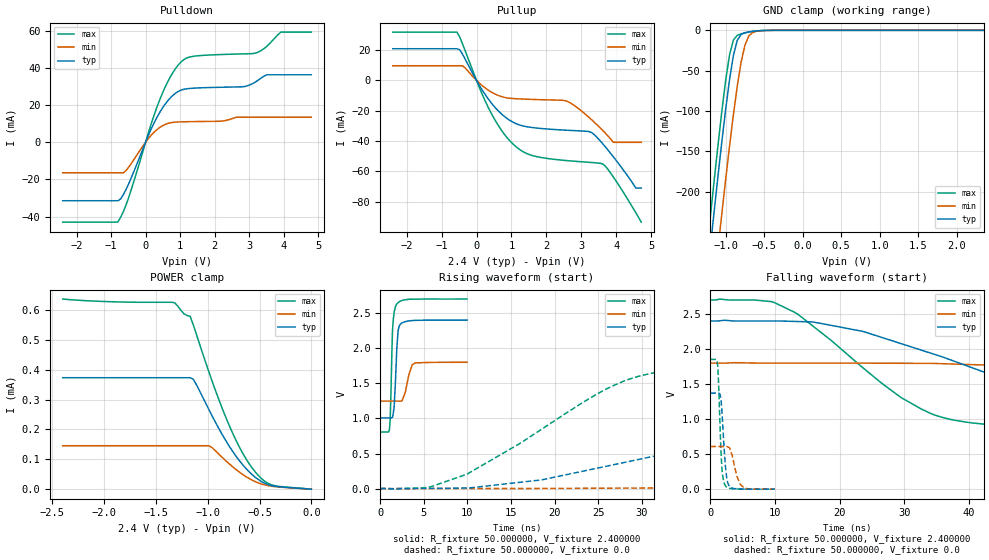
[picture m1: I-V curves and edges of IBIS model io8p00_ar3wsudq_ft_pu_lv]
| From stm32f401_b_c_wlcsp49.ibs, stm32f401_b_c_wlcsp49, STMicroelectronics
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|   Model io8p00_ar3wsudq_ft_pu_lv
[Model]  io8p00_ar3wsudq_ft_pu_lv
Model_type I/O
Polarity   Non-Inverting
Enable   Active-Low
Vinl =   0.720000V
Vinh =   1.680000V
Vmeas =  1.200000V
Cref =   50.000000pF
Rref =   100.000000M
Vref =   0.0V
C_comp   3.740200pF   3.683500pF   3.822900pF
[Temperature Range]   25.000000   0.125000k   -40.000000
[Pullup Reference]   2.400000V   1.800000V   2.700000V
[Pulldown Reference]   0.0V   0.0V   0.0V
[POWER Clamp Reference]   2.400000V   1.800000V   2.700000V
[GND Clamp Reference]   0.0V   0.0V   0.0V
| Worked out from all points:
|   slope of the pulldown table from 0 to 0.36 V, typ, clamps not added: 25 ohm
|   slope of the pullup table from 0 to 0.36 V, typ, clamps not added: 27.7 ohm
|   GND clamp passes 1 mA (typ) near -0.62 V on its own axis
|   rising waveform, R_fixture 50.000000, V_fixture 2.400000: 20-80 % time 328ps typ, 642ps min, 254ps max; typ from 1.01 V to 2.4 V
|   rising waveform, R_fixture 50.000000, V_fixture 0.0: 20-80 % time 32.3ns typ, 81.1ns min, 14.8ns max; typ from 0.001 V to 1.37 V
|   falling waveform, R_fixture 50.000000, V_fixture 2.400000: 20-80 % time 29.5ns typ, 74.1ns min, 15.9ns max; typ from 2.4 V to 1.01 V
|   falling waveform, R_fixture 50.000000, V_fixture 0.0: 20-80 % time 593ps typ, 1.03ns min, 461ps max; typ from 1.37 V to 0.001 V
[Pulldown]
|Voltage   I(typ)   I(min)   I(max)
-2.4V     -31.47mA   -16.45mA   -43.01mA
-800mV    -31.47mA   -16.45mA   -42.85mA
-480mV    -21.98mA   -13.17mA   -29.21mA
80mV      3.63mA     1.966mA    5.014mA
480mV     18.16mA    8.738mA    26.02mA
800mV     25.38mA    10.72mA    37.77mA
1.12V     28.53mA    11.02mA    44.6mA
2.8V      29.84mA    13.47mA    47.53mA
3.2V      32.6mA     13.47mA    48.03mA
3.52V     36.29mA    13.47mA    51.75mA
3.92V     36.29mA    13.47mA    59.26mA
4.8V      36.29mA    13.47mA    59.26mA
[Pullup]
|Voltage   I(typ)   I(min)   I(max)
-2.4V     20.87mA    9.66mA     31.87mA
-560mV    20.87mA    9.66mA     31.87mA
-400mV    17.27mA    9.66mA     24.06mA
320mV     -11.75mA   -6.207mA   -17.08mA
960mV     -26.47mA   -11.82mA   -40.02mA
1.52V     -30.88mA   -12.51mA   -49.05mA
2.56V     -32.88mA   -13.52mA   -52.9mA
3.28V     -34.25mA   -25.63mA   -54.17mA
3.6V      -41.44mA   -32.74mA   -55.02mA
3.92V     -50.46mA   -40.9mA    -63.78mA
4.56V     -71.1mA    -40.9mA    -87.25mA
4.72V     -71.1mA    -40.9mA    -93.6mA
[GND_clamp]
|Voltage   I(typ)   I(min)   I(max)
-2.4V     -1.43A     -1.515A    -1.4A
-1.25V    -315.9mA   -407.2mA   -278.2mA
-1.2V     -270.1mA   -361.3mA   -232.1mA
-1.15V    -225mA     -316mA     -186.8mA
-1.1V     -180.9mA   -271.3mA   -142.7mA
-1.05V    -138.2mA   -227.5mA   -100.5mA
-950mV    -61.14mA   -143.6mA   -30.43mA
-900mV    -31.23mA   -104.7mA   -12.14mA
-850mV    -12.49mA   -69.4mA    -6.221mA
-750mV    -2.898mA   -18.35mA   -3.18mA
-600mV    -750.2uA   -1.218mA   -738.3uA
2.35V     0A         0A         0A
[POWER_clamp]
|Voltage   I(typ)   I(min)   I(max)
-2.4V     373.1uA    145.5uA    636.5uA
-1.32V    373.1uA    145.5uA    624.2uA
-1.23V    373.1uA    145.5uA    587.2uA
-1.17V    373.1uA    145.5uA    579uA
-1.14V    368.3uA    145.5uA    550.7uA
-990mV    267.3uA    145.5uA    393.9uA
-810mV    153.6uA    90.29uA    227.7uA
-690mV    93.37uA    55.97uA    138.2uA
-570mV    48.37uA    29.94uA    70.44uA
-480mV    25.27uA    17.04uA    35.17uA
-390mV    12.49uA    10.18uA    15.16uA
0V        0A         0A         0A
[Ramp]
| variable   typ   min   max
dV/dt_r  0.82195/32.25554n   0.36273/83.56868n   1.11101/14.76657n
dV/dt_f  0.83610/29.45514n   0.32700/79.34821n   1.13654/15.88322n
R_load = 50.000000
[Rising Waveform]
R_fixture= 50.000000
V_fixture= 2.400000
V_fixture_min= 1.800000
V_fixture_max= 2.700000
|time   V(typ)   V(min)   V(max)
0s        1.007V     1.247V     805.7mV
1.041ns   1.007V     1.247V     832mV
1.141ns   1.007V     1.247V     1.005V
1.421ns   1.02V      1.247V     2.287V
1.582ns   1.147V     1.247V     2.499V
1.862ns   1.888V     1.247V     2.622V
2.062ns   2.261V     1.246V     2.651V
2.583ns   2.366V     1.278V     2.684V
3.684ns   2.394V     1.767V     2.698V
9.97ns    2.4V       1.8V       2.7V
[Rising Waveform]
R_fixture= 50.000000
V_fixture= 0.0
V_fixture_min= 0.0
V_fixture_max= 0.0
|time   V(typ)   V(min)   V(max)
0s        880.4uV    840.3uV    911.2uV
5.506ns   2.73mV     1.829mV    17.1mV
10.01ns   9.424mV    1.89mV     210.3mV
26.53ns   334mV      6.55mV     1.454V
30.03ns   425.5mV    8.355mV    1.612V
37.04ns   629.5mV    25.26mV    1.746V
64.06ns   1.224V     116.1mV    1.842V
80.08ns   1.317V     195.6mV    1.848V
147.6ns   1.369V     493.3mV    1.853V
249.2ns   1.371V     610.3mV    1.852V
[Falling Waveform]
R_fixture= 50.000000
V_fixture= 2.400000
V_fixture_min= 1.800000
V_fixture_max= 2.700000
|time   V(typ)   V(min)   V(max)
0s        2.4V       1.8V       2.7V
10.01ns   2.4V       1.8V       2.659V
13.51ns   2.393V     1.8V       2.498V
23.52ns   2.253V     1.799V     1.739V
32.53ns   1.987V     1.796V     1.149V
44.54ns   1.598V     1.766V     908.1mV
61.06ns   1.232V     1.706V     847.6mV
85.59ns   1.08V      1.567V     819.8mV
125.1ns   1.028V     1.382V     808.3mV
249.2ns   1.007V     1.247V     805.7mV
[Falling Waveform]
R_fixture= 50.000000
V_fixture= 0.0
V_fixture_min= 0.0
V_fixture_max= 0.0
|time   V(typ)   V(min)   V(max)
0s        1.371V     610.3mV    1.852V
1.141ns   1.371V     610.2mV    1.762V
1.722ns   1.207V     609.9mV    416.8mV
1.942ns   891.9mV    609.7mV    180.2mV
2.302ns   378.6mV    610.7mV    55.54mV
2.543ns   165.4mV    610.4mV    29.7mV
2.943ns   44.65mV    593mV      13.01mV
4.104ns   5.257mV    187.2mV    3.08mV
5.285ns   2.013mV    14.59mV    1.544mV
9.97ns    880.4uV    840.3uV    911.2uV
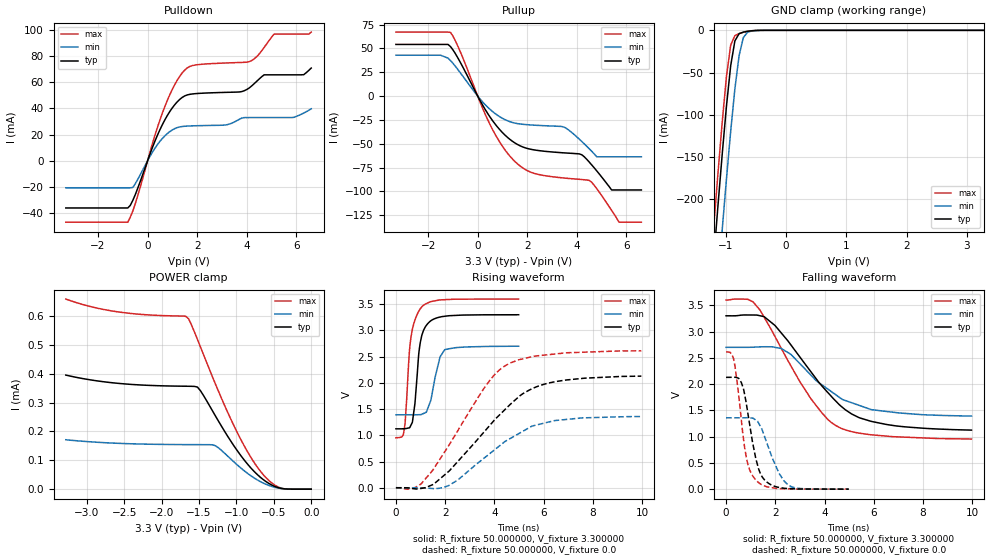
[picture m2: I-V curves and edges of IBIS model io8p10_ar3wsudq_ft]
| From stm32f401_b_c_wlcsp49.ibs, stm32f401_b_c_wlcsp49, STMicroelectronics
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|   Model io8p10_ar3wsudq_ft
[Model]  io8p10_ar3wsudq_ft
Model_type I/O
Polarity   Non-Inverting
Enable   Active-Low
Vinl =   0.990000V
Vinh =   2.310000V
Vmeas =  1.650000V
Cref =   40.000000pF
Rref =   100.000000M
Vref =   0.0V
C_comp   3.843100pF   3.761700pF   3.937000pF
[Temperature Range]   25.000000   0.125000k   -40.000000
[Pullup Reference]   3.300000V   2.700000V   3.600000V
[Pulldown Reference]   0.0V   0.0V   0.0V
[POWER Clamp Reference]   3.300000V   2.700000V   3.600000V
[GND Clamp Reference]   0.0V   0.0V   0.0V
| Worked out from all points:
|   slope of the pulldown table from 0 to 0.495 V, typ, clamps not added: 20.9 ohm
|   slope of the pullup table from 0 to 0.495 V, typ, clamps not added: 22.6 ohm
|   GND clamp passes 1 mA (typ) near -0.62 V on its own axis
|   rising waveform, R_fixture 50.000000, V_fixture 3.300000: 20-80 % time 273ps typ, 357ps min, 284ps max; typ from 1.12 V to 3.3 V
|   rising waveform, R_fixture 50.000000, V_fixture 0.0: 20-80 % time 2.54ns typ, 2.37ns min, 2.13ns max; typ from 0 V to 2.13 V
|   falling waveform, R_fixture 50.000000, V_fixture 3.300000: 20-80 % time 2.29ns typ, 2.15ns min, 2.04ns max; typ from 3.3 V to 1.12 V
|   falling waveform, R_fixture 50.000000, V_fixture 0.0: 20-80 % time 504ps typ, 694ps min, 425ps max; typ from 2.13 V to 0 V
[Pulldown]
|Voltage   I(typ)   I(min)   I(max)
-3.3V     -36.18mA   -20.77mA   -47.07mA
-800mV    -36.18mA   -20.77mA   -47.07mA
-600mV    -30.5mA    -20.52mA   -38.69mA
700mV     31.4mA     19.11mA    41.71mA
1.2V      45.15mA    25.37mA    61.75mA
1.6V      50.35mA    26.5mA     71.06mA
3.1V      52.28mA    27.26mA    74.76mA
4.1V      55.71mA    33.01mA    75.8mA
4.7V      65.73mA    33.01mA    86.69mA
5.1V      65.73mA    33.01mA    96.9mA
6.3V      65.85mA    36.5mA     96.9mA
6.6V      70.91mA    39.71mA    98.45mA
[Pullup]
|Voltage   I(typ)   I(min)   I(max)
-3.3V     54.22mA    42.91mA    67.16mA
-1.1V     51.99mA    37.3mA     66.88mA
500mV     -22.07mA   -14mA      -30.03mA
1.5V      -49.1mA    -28.3mA    -68.56mA
2.2V      -56.05mA   -30.32mA   -80.35mA
3.5V      -59.53mA   -32.72mA   -85.92mA
4.2V      -61.52mA   -47.62mA   -87.46mA
4.5V      -69.21mA   -55.27mA   -88.43mA
4.8V      -78.37mA   -63.6mA    -97.01mA
5.4V      -98.4mA    -63.6mA    -119.7mA
5.7V      -98.4mA    -63.6mA    -132.2mA
6.6V      -98.4mA    -63.6mA    -132.2mA
[GND_clamp]
|Voltage   I(typ)   I(min)   I(max)
-3.3V     -2.327A    -2.405A    -2.301A
-1.2V     -270.2mA   -361.4mA   -232.1mA
-1.13V    -207.3mA   -298.1mA   -169mA
-1.06V    -146.7mA   -236.2mA   -108.8mA
-990mV    -90.18mA   -176.4mA   -54.96mA
-920mV    -42.21mA   -120mA     -17.68mA
-850mV    -12.57mA   -69.47mA   -6.265mA
-780mV    -3.971mA   -30.01mA   -3.886mA
-710mV    -2.1mA     -8.615mA   -2.382mA
-640mV    -1.148mA   -2.283mA   -1.22mA
-570mV    -524uA     -821.5uA   -476.8uA
3.28V     0A         0A         0A
[POWER_clamp]
|Voltage   I(typ)   I(min)   I(max)
-3.28V    395.3uA    171.3uA    658.7uA
-2.6V     367.1uA    159uA      614.9uA
-1.68V    356.7uA    154.4uA    599.4uA
-1.64V    356.5uA    154.4uA    590.8uA
-1.52V    353.6uA    154.3uA    518.3uA
-1.48V    341.1uA    154.2uA    492.3uA
-1.28V    253.6uA    150.4uA    364.2uA
-960mV    123.1uA    77.56uA    181.6uA
-720mV    50.52uA    32.03uA    76.18uA
-560mV    18.94uA    12.27uA    28.65uA
-440mV    5.104uA    3.69uA     7.327uA
0V        0A         0A         0A
[Ramp]
| variable   typ   min   max
dV/dt_r  1.26690/2.54223n   0.81108/2.36850n   1.56426/2.13118n
dV/dt_f  1.28262/2.27090n   0.77586/2.13620n   1.57490/2.04549n
R_load = 50.000000
[Rising Waveform]
R_fixture= 50.000000
V_fixture= 3.300000
V_fixture_min= 2.700000
V_fixture_max= 3.600000
|time   V(typ)   V(min)   V(max)
0s        1.124V     1.392V     954.3mV
300.3ps   1.126V     1.392V     1.007V
370.4ps   1.127V     1.392V     1.219V
550.6ps   1.144V     1.392V     2.616V
670.7ps   1.255V     1.392V     3.026V
1.031ns   2.862V     1.397V     3.44V
1.411ns   3.183V     1.66V      3.549V
1.792ns   3.256V     2.493V     3.583V
1.982ns   3.271V     2.633V     3.587V
4.985ns   3.3V       2.7V       3.599V
[Rising Waveform]
R_fixture= 50.000000
V_fixture= 0.0
V_fixture_min= 0.0
V_fixture_max= 0.0
|time   V(typ)   V(min)   V(max)
0s        344.1uV    196.6uV    677uV
480.5ps   -2.556mV   137.5uV    -26.14mV
1.021ns   -13.38mV   -1.475mV   72.35mV
1.522ns   64.62mV    -15.8mV    352.4mV
2.142ns   310.9mV    41.11mV    803mV
3.644ns   1.098V     588.7mV    1.942V
4.484ns   1.517V     897mV      2.34V
5.165ns   1.797V     1.079V     2.46V
6.266ns   2.003V     1.261V     2.542V
9.97ns    2.129V     1.359V     2.612V
[Falling Waveform]
R_fixture= 50.000000
V_fixture= 3.300000
V_fixture_min= 2.700000
V_fixture_max= 3.600000
|time   V(typ)   V(min)   V(max)
0s        3.3V       2.7V       3.599V
1.101ns   3.315V     2.702V     3.564V
1.542ns   3.284V     2.71V      3.277V
2.242ns   2.974V     2.678V     2.682V
2.643ns   2.741V     2.561V     2.34V
3.463ns   2.224V     2.162V     1.711V
4.464ns   1.674V     1.794V     1.21V
5.105ns   1.43V      1.645V     1.095V
5.906ns   1.29V      1.513V     1.035V
9.97ns    1.124V     1.392V     954.3mV
[Falling Waveform]
R_fixture= 50.000000
V_fixture= 0.0
V_fixture_min= 0.0
V_fixture_max= 0.0
|time   V(typ)   V(min)   V(max)
0s        2.129V     1.359V     2.612V
300.3ps   2.13V      1.359V     2.491V
470.5ps   2.117V     1.358V     1.964V
620.6ps   2.03V      1.358V     1.32V
850.9ps   1.548V     1.36V      540.8mV
1.201ns   600mV      1.318V     179.8mV
1.582ns   167.7mV    978.7mV    58.82mV
2.162ns   32.73mV    293.8mV    11.15mV
2.472ns   13.88mV    101.1mV    7.345mV
4.985ns   344.1uV    196.6uV    677uV
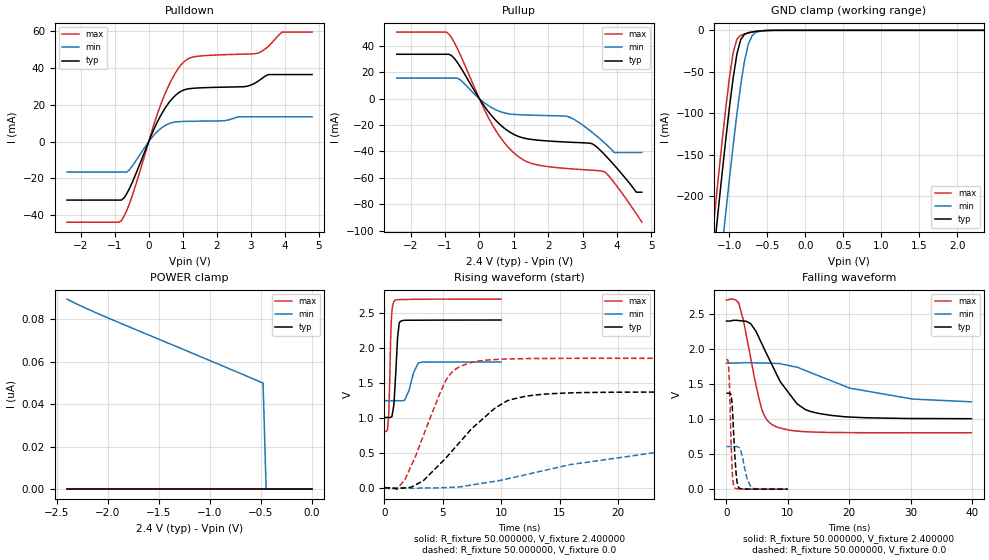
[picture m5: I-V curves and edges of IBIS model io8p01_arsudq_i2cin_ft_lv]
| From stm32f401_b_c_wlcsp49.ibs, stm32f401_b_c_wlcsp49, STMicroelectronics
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|   Model io8p01_arsudq_i2cin_ft_lv
[Model]  io8p01_arsudq_i2cin_ft_lv
Model_type I/O
Polarity   Non-Inverting
Enable   Active-Low
Vinl =   0.720000V
Vinh =   1.680000V
Vmeas =  1.200000V
Cref =   50.000000pF
Rref =   100.000000M
Vref =   0.0V
C_comp   2.230300pF   2.174000pF   2.332300pF
[Temperature Range]   25.000000   0.125000k   -40.000000
[Pullup Reference]   2.400000V   1.800000V   2.700000V
[Pulldown Reference]   0.0V   0.0V   0.0V
[POWER Clamp Reference]   2.400000V   1.800000V   2.700000V
[GND Clamp Reference]   0.0V   0.0V   0.0V
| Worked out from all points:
|   slope of the pulldown table from 0 to 0.36 V, typ, clamps not added: 25 ohm
|   slope of the pullup table from 0 to 0.36 V, typ, clamps not added: 27.7 ohm
|   GND clamp passes 1 mA (typ) near -0.62 V on its own axis
|   rising waveform, R_fixture 50.000000, V_fixture 2.400000: 20-80 % time 273ps typ, 605ps min, 184ps max; typ from 1.01 V to 2.4 V
|   rising waveform, R_fixture 50.000000, V_fixture 0.0: 20-80 % time 4.8ns typ, 12.1ns min, 2.64ns max; typ from 0 V to 1.37 V
|   falling waveform, R_fixture 50.000000, V_fixture 2.400000: 20-80 % time 5.39ns typ, 12.7ns min, 2.67ns max; typ from 2.4 V to 1.01 V
|   falling waveform, R_fixture 50.000000, V_fixture 0.0: 20-80 % time 525ps typ, 974ps min, 385ps max; typ from 1.37 V to 0 V
[Pulldown]
|Voltage   I(typ)   I(min)   I(max)
-2.4V     -31.73mA   -16.51mA   -43.74mA
-800mV    -31.73mA   -16.51mA   -42.87mA
-480mV    -21.98mA   -13.17mA   -29.21mA
80mV      3.63mA     1.966mA    5.014mA
480mV     18.16mA    8.738mA    26.02mA
800mV     25.38mA    10.72mA    37.77mA
1.12V     28.53mA    11.02mA    44.6mA
2.8V      29.84mA    13.49mA    47.53mA
3.2V      32.65mA    13.49mA    48.05mA
3.52V     36.43mA    13.49mA    51.84mA
3.92V     36.43mA    13.49mA    59.49mA
4.8V      36.43mA    13.49mA    59.49mA
[Pullup]
|Voltage   I(typ)   I(min)   I(max)
-2.4V     33.57mA    15.56mA    50.37mA
-960mV    33.57mA    15.56mA    50.37mA
-560mV    24.29mA    14.3mA     33.55mA
320mV     -11.75mA   -6.207mA   -17.08mA
960mV     -26.47mA   -11.82mA   -40.02mA
1.52V     -30.88mA   -12.51mA   -49.05mA
2.56V     -32.88mA   -13.48mA   -52.9mA
3.28V     -34.19mA   -25.52mA   -54.18mA
3.6V      -41.31mA   -32.62mA   -54.97mA
3.92V     -50.33mA   -40.8mA    -63.62mA
4.56V     -70.8mA    -40.8mA    -87.07mA
4.72V     -70.8mA    -40.8mA    -93.5mA
[GND_clamp]
|Voltage   I(typ)   I(min)   I(max)
-2.4V     -1.424A    -1.508A    -1.393A
-1.25V    -311.2mA   -401.9mA   -273.3mA
-1.2V     -265.4mA   -356.1mA   -227.2mA
-1.15V    -220.4mA   -310.8mA   -181.9mA
-1.1V     -176.3mA   -266.2mA   -137.9mA
-1.05V    -133.8mA   -222.5mA   -95.87mA
-950mV    -57.3mA    -138.9mA   -26.98mA
-900mV    -28.27mA   -100.4mA   -10.59mA
-850mV    -11.01mA   -65.54mA   -5.958mA
-750mV    -2.834mA   -16.5mA    -3.178mA
-600mV    -750uA     -1.164mA   -738.3uA
2.35V     0A         0A         0A
[POWER_clamp]
|Voltage   I(typ)   I(min)   I(max)
-2.4V     0A         89.62nA    0A
-2.04V    0A         81.57nA    0A
-480mV    0A         50.01nA    0A
-450mV    0A         0A         0A
0V        0A         0A         0A
[Ramp]
| variable   typ   min   max
dV/dt_r  0.82218/4.79826n   0.38452/12.99247n   1.11108/2.64218n
dV/dt_f  0.83670/5.39609n   0.32334/13.40759n   1.13764/2.66912n
R_load = 50.000000
[Rising Waveform]
R_fixture= 50.000000
V_fixture= 2.400000
V_fixture_min= 1.800000
V_fixture_max= 2.700000
|time   V(typ)   V(min)   V(max)
0s        1.006V     1.247V     804.6mV
240.2ps   1.006V     1.247V     825.4mV
340.3ps   1.006V     1.247V     987.7mV
600.6ps   1.015V     1.247V     2.441V
860.9ps   1.347V     1.247V     2.675V
1.121ns   2.148V     1.247V     2.691V
1.381ns   2.382V     1.245V     2.693V
1.722ns   2.395V     1.252V     2.694V
2.903ns   2.397V     1.786V     2.697V
9.97ns    2.4V       1.8V       2.7V
[Rising Waveform]
R_fixture= 50.000000
V_fixture= 0.0
V_fixture_min= 0.0
V_fixture_max= 0.0
|time   V(typ)   V(min)   V(max)
0s        178uV      73.83uV    433.7uV
1.201ns   -14.27mV   132.9uV    8.824mV
1.762ns   -1.066mV   -612.4uV   121.8mV
3.283ns   97.62mV    -603.1uV   726mV
5.125ns   404.2mV    3.4mV      1.499V
7.287ns   814mV      36.02mV    1.786V
10.49ns   1.245V     127.9mV    1.843V
13.21ns   1.333V     231mV      1.85V
24.82ns   1.37V      543.3mV    1.852V
39.88ns   1.37V      609mV      1.852V
[Falling Waveform]
R_fixture= 50.000000
V_fixture= 2.400000
V_fixture_min= 1.800000
V_fixture_max= 2.700000
|time   V(typ)   V(min)   V(max)
0s        2.4V       1.8V       2.7V
2.002ns   2.407V     1.801V     2.655V
2.803ns   2.4V       1.805V     2.39V
3.924ns   2.363V     1.805V     1.881V
5.766ns   2.075V     1.8V       1.138V
7.688ns   1.726V     1.796V     908.6mV
11.45ns   1.222V     1.741V     829.3mV
13.85ns   1.106V     1.659V     816.2mV
20.1ns    1.03V      1.442V     807.2mV
39.88ns   1.006V     1.247V     804.6mV
[Falling Waveform]
R_fixture= 50.000000
V_fixture= 0.0
V_fixture_min= 0.0
V_fixture_max= 0.0
|time   V(typ)   V(min)   V(max)
0s        1.37V      609mV      1.852V
380.4ps   1.37V      609.1mV    1.718V
480.5ps   1.37V      609mV      1.522V
880.9ps   1.254V     608.8mV    366.6mV
1.041ns   1.034V     608.6mV    132.3mV
1.261ns   650.2mV    608.4mV    36.07mV
1.702ns   116.9mV    610.4mV    6.022mV
2.062ns   18.63mV    592.8mV    3.699mV
3.864ns   1.479mV    51.48mV    1.362mV
9.97ns    178uV      73.83uV    433.7uV
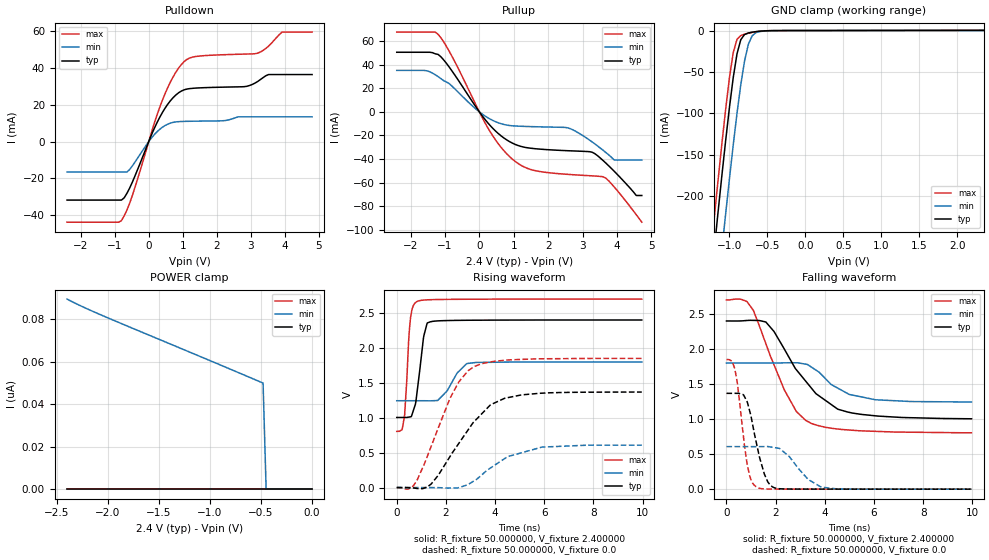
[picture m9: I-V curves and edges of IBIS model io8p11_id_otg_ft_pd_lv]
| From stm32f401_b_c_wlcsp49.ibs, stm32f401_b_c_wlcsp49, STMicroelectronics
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|   Model io8p11_id_otg_ft_pd_lv
[Model]  io8p11_id_otg_ft_pd_lv
Model_type I/O
Polarity   Non-Inverting
Enable   Active-Low
Vinl =   0.720000V
Vinh =   1.680000V
Vmeas =  1.200000V
Cref =   30.000000pF
Rref =   100.000000M
Vref =   0.0V
C_comp   2.229800pF   2.169700pF   2.325100pF
[Temperature Range]   25.000000   0.125000k   -40.000000
[Pullup Reference]   2.400000V   1.800000V   2.700000V
[Pulldown Reference]   0.0V   0.0V   0.0V
[POWER Clamp Reference]   2.400000V   1.800000V   2.700000V
[GND Clamp Reference]   0.0V   0.0V   0.0V
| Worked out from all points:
|   slope of the pulldown table from 0 to 0.36 V, typ, clamps not added: 25 ohm
|   slope of the pullup table from 0 to 0.36 V, typ, clamps not added: 27.7 ohm
|   GND clamp passes 1 mA (typ) near -0.62 V on its own axis
|   rising waveform, R_fixture 50.000000, V_fixture 2.400000: 20-80 % time 282ps typ, 629ps min, 184ps max; typ from 1 V to 2.4 V
|   rising waveform, R_fixture 50.000000, V_fixture 0.0: 20-80 % time 1.7ns typ, 1.69ns min, 1.31ns max; typ from 0 V to 1.37 V
|   falling waveform, R_fixture 50.000000, V_fixture 2.400000: 20-80 % time 1.81ns typ, 1.29ns min, 1.38ns max; typ from 2.4 V to 1 V
|   falling waveform, R_fixture 50.000000, V_fixture 0.0: 20-80 % time 533ps typ, 923ps min, 382ps max; typ from 1.37 V to 0 V
[Pulldown]
|Voltage   I(typ)   I(min)   I(max)
-2.4V     -31.73mA   -16.51mA   -43.74mA
-800mV    -31.73mA   -16.51mA   -42.87mA
-480mV    -21.97mA   -13.17mA   -29.2mA
80mV      3.629mA    1.966mA    5.013mA
480mV     18.15mA    8.737mA    26.01mA
800mV     25.37mA    10.71mA    37.77mA
1.12V     28.53mA    11.02mA    44.6mA
2.8V      29.83mA    13.48mA    47.51mA
3.2V      32.64mA    13.48mA    48.03mA
3.52V     36.41mA    13.48mA    51.82mA
3.92V     36.41mA    13.48mA    59.47mA
4.8V      36.41mA    13.48mA    59.47mA
[Pullup]
|Voltage   I(typ)   I(min)   I(max)
-2.4V     50.44mA    35.08mA    67.52mA
-1.52V    50.44mA    34.74mA    67.52mA
-1.2V     48.63mA    29.87mA    65.67mA
320mV     -11.75mA   -6.207mA   -17.08mA
1.04V     -27.53mA   -11.97mA   -41.9mA
1.6V      -31.13mA   -12.58mA   -49.63mA
2.56V     -32.88mA   -13.48mA   -52.9mA
3.28V     -34.19mA   -25.52mA   -54.18mA
3.6V      -41.31mA   -32.61mA   -54.98mA
3.92V     -50.32mA   -40.8mA    -63.62mA
4.56V     -70.8mA    -40.8mA    -87.08mA
4.72V     -70.8mA    -40.8mA    -93.4mA
[GND_clamp]
|Voltage   I(typ)   I(min)   I(max)
-2.4V     -1.423A    -1.508A    -1.392A
-1.25V    -311.2mA   -401.9mA   -273.3mA
-1.2V     -265.4mA   -356.1mA   -227.2mA
-1.15V    -220.4mA   -310.8mA   -181.9mA
-1.1V     -176.3mA   -266.2mA   -137.9mA
-1.05V    -133.8mA   -222.5mA   -95.89mA
-950mV    -57.33mA   -138.9mA   -27.03mA
-900mV    -28.31mA   -100.4mA   -10.67mA
-850mV    -11.07mA   -65.56mA   -6.047mA
-750mV    -2.904mA   -16.55mA   -3.26mA
-600mV    -808.2uA   -1.212mA   -806.8uA
2.35V     242.6uA    152uA      283.9uA
[POWER_clamp]
|Voltage   I(typ)   I(min)   I(max)
-2.4V     0A         89.62nA    0A
-2.04V    0A         81.58nA    0A
-480mV    0A         50.01nA    0A
-450mV    0A         0A         0A
0V        0A         0A         0A
[Ramp]
| variable   typ   min   max
dV/dt_r  0.81918/1.69832n   0.36251/1.67494n   1.10832/1.31294n
dV/dt_f  0.83238/1.80251n   0.33384/1.29946n   1.13446/1.37566n
R_load = 50.000000
[Rising Waveform]
R_fixture= 50.000000
V_fixture= 2.400000
V_fixture_min= 1.800000
V_fixture_max= 2.700000
|time   V(typ)   V(min)   V(max)
0s        1.003V     1.242V     802.9mV
220.2ps   1.003V     1.242V     830.1mV
320.3ps   1.002V     1.242V     1.034V
480.5ps   1.007V     1.242V     2.072V
560.6ps   1.011V     1.242V     2.427V
840.8ps   1.404V     1.242V     2.662V
1.101ns   2.168V     1.241V     2.681V
1.361ns   2.369V     1.24V      2.686V
2.863ns   2.392V     1.773V     2.693V
9.97ns    2.396V     1.796V     2.695V
[Rising Waveform]
R_fixture= 50.000000
V_fixture= 0.0
V_fixture_min= 0.0
V_fixture_max= 0.0
|time   V(typ)   V(min)   V(max)
0s        165.5uV    65.51uV    261.4uV
660.7ps   -5.461mV   52.14uV    19.63mV
1.401ns   50.62mV    101.3uV    590.1mV
2.182ns   452.3mV    -6.999mV   1.286V
2.523ns   630.2mV    -985.8uV   1.509V
3.123ns   933mV      90.59mV    1.724V
3.804ns   1.18V      277.5mV    1.796V
4.384ns   1.276V     412.8mV    1.82V
5.906ns   1.349V     578.4mV    1.841V
9.97ns    1.366V     606.4mV    1.847V
[Falling Waveform]
R_fixture= 50.000000
V_fixture= 2.400000
V_fixture_min= 1.800000
V_fixture_max= 2.700000
|time   V(typ)   V(min)   V(max)
0s        2.396V     1.796V     2.695V
600.6ps   2.397V     1.796V     2.705V
1.081ns   2.405V     1.796V     2.555V
1.602ns   2.382V     1.796V     2.074V
2.362ns   1.991V     1.8V       1.41V
2.843ns   1.702V     1.801V     1.107V
3.223ns   1.539V     1.781V     980.4mV
3.644ns   1.36V      1.696V     914.9mV
4.925ns   1.1V       1.363V     844.3mV
9.97ns    1.003V     1.242V     802.9mV
[Falling Waveform]
R_fixture= 50.000000
V_fixture= 0.0
V_fixture_min= 0.0
V_fixture_max= 0.0
|time   V(typ)   V(min)   V(max)
0s        1.366V     606.4mV    1.847V
340.3ps   1.366V     606.5mV    1.714V
440.4ps   1.365V     606.4mV    1.518V
700.7ps   1.34V      606.4mV    720.9mV
940.9ps   1.119V     606.2mV    195.7mV
1.261ns   589.4mV    606.1mV    23.79mV
1.682ns   104.1mV    607.2mV    2.56mV
2.042ns   11.47mV    587.4mV    1.581mV
3.864ns   910uV      29.08mV    757.5uV
9.97ns    165.5uV    65.51uV    261.4uV
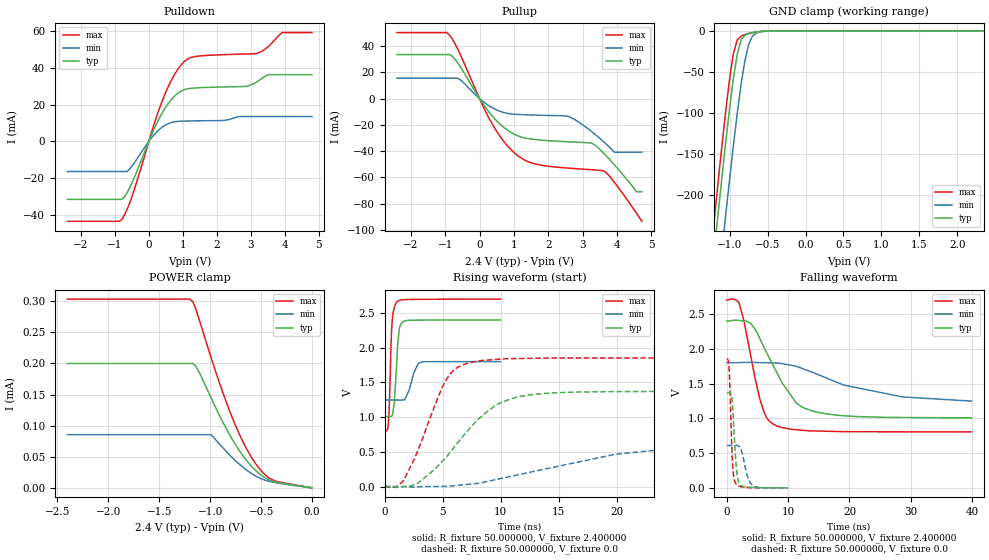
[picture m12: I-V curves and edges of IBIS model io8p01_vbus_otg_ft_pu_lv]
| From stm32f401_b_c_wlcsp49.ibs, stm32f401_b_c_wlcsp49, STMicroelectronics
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|   Model io8p01_vbus_otg_ft_pu_lv
[Model]  io8p01_vbus_otg_ft_pu_lv
Model_type I/O
Polarity   Non-Inverting
Enable   Active-Low
Vinl =   0.720000V
Vinh =   1.680000V
Vmeas =  1.200000V
Cref =   50.000000pF
Rref =   100.000000M
Vref =   0.0V
C_comp   3.193600pF   3.100000pF   3.332100pF
[Temperature Range]   25.000000   0.125000k   -40.000000
[Pullup Reference]   2.400000V   1.800000V   2.700000V
[Pulldown Reference]   0.0V   0.0V   0.0V
[POWER Clamp Reference]   2.400000V   1.800000V   2.700000V
[GND Clamp Reference]   0.0V   0.0V   0.0V
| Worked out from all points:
|   slope of the pulldown table from 0 to 0.36 V, typ, clamps not added: 25 ohm
|   slope of the pullup table from 0 to 0.36 V, typ, clamps not added: 27.7 ohm
|   GND clamp passes 1 mA (typ) near -0.61 V on its own axis
|   rising waveform, R_fixture 50.000000, V_fixture 2.400000: 20-80 % time 309ps typ, 629ps min, 223ps max; typ from 1.01 V to 2.4 V
|   rising waveform, R_fixture 50.000000, V_fixture 0.0: 20-80 % time 4.51ns typ, 11ns min, 2.64ns max; typ from 0.001 V to 1.37 V
|   falling waveform, R_fixture 50.000000, V_fixture 2.400000: 20-80 % time 5.28ns typ, 12.7ns min, 2.76ns max; typ from 2.4 V to 1.01 V
|   falling waveform, R_fixture 50.000000, V_fixture 0.0: 20-80 % time 576ps typ, 1.04ns min, 436ps max; typ from 1.37 V to 0.001 V
[Pulldown]
|Voltage   I(typ)   I(min)   I(max)
-2.4V     -31.69mA   -16.5mA    -43.66mA
-800mV    -31.69mA   -16.5mA    -42.82mA
-480mV    -21.96mA   -13.17mA   -29.19mA
80mV      3.63mA     1.966mA    5.014mA
480mV     18.16mA    8.738mA    26.02mA
800mV     25.38mA    10.72mA    37.77mA
1.12V     28.53mA    11.02mA    44.6mA
2.8V      29.84mA    13.46mA    47.53mA
3.2V      32.6mA     13.46mA    48.03mA
3.52V     36.28mA    13.46mA    51.75mA
3.92V     36.28mA    13.46mA    59.24mA
4.8V      36.28mA    13.46mA    59.24mA
[Pullup]
|Voltage   I(typ)   I(min)   I(max)
-2.4V     33.5mA     15.55mA    50.22mA
-960mV    33.5mA     15.55mA    50.22mA
-560mV    24.27mA    14.29mA    33.52mA
320mV     -11.75mA   -6.207mA   -17.08mA
960mV     -26.47mA   -11.82mA   -40.02mA
1.52V     -30.88mA   -12.51mA   -49.05mA
2.56V     -32.88mA   -13.49mA   -52.9mA
3.28V     -34.19mA   -25.52mA   -54.18mA
3.6V      -41.31mA   -32.62mA   -54.98mA
3.92V     -50.32mA   -40.8mA    -63.62mA
4.56V     -70.9mA    -40.8mA    -87.07mA
4.72V     -70.9mA    -40.8mA    -93.4mA
[GND_clamp]
|Voltage   I(typ)   I(min)   I(max)
-2.4V     -1.425A    -1.509A    -1.394A
-1.25V    -311.3mA   -401.9mA   -273.4mA
-1.2V     -265.5mA   -356.1mA   -227.3mA
-1.15V    -220.5mA   -310.9mA   -182mA
-1.1V     -176.4mA   -266.2mA   -138mA
-1.05V    -133.9mA   -222.5mA   -96.06mA
-950mV    -57.51mA   -139mA     -27.35mA
-900mV    -28.55mA   -100.5mA   -11.03mA
-850mV    -11.33mA   -65.67mA   -6.322mA
-750mV    -3.069mA   -16.69mA   -3.425mA
-600mV    -864.6uA   -1.294mA   -852.2uA
2.35V     0A         0A         0A
[POWER_clamp]
|Voltage   I(typ)   I(min)   I(max)
-2.4V     200uA      85.42uA    303.5uA
-1.2V     200uA      85.42uA    303.5uA
-1.17V    200uA      85.42uA    299.5uA
-1.14V    195.7uA    85.42uA    287.5uA
-990mV    144.6uA    85.42uA    209.3uA
-870mV    104.1uA    63.64uA    150.8uA
-780mV    77.28uA    48.22uA    111.8uA
-660mV    47.71uA    30.77uA    68.21uA
-570mV    30.64uA    20.64uA    42.8uA
-480mV    18.19uA    13.46uA    24.07uA
-390mV    10.91uA    9.255uA    13.01uA
0V        0A         0A         0A
[Ramp]
| variable   typ   min   max
dV/dt_r  0.82225/4.50574n   0.36627/11.20535n   1.11077/2.63350n
dV/dt_f  0.83592/5.28187n   0.32220/13.02593n   1.13647/2.75354n
R_load = 50.000000
[Rising Waveform]
R_fixture= 50.000000
V_fixture= 2.400000
V_fixture_min= 1.800000
V_fixture_max= 2.700000
|time   V(typ)   V(min)   V(max)
0s        1.007V     1.247V     805.7mV
340.3ps   1.007V     1.247V     973.1mV
560.6ps   1.013V     1.247V     2.147V
640.6ps   1.025V     1.247V     2.381V
800.8ps   1.169V     1.247V     2.569V
1.041ns   1.827V     1.247V     2.658V
1.261ns   2.281V     1.247V     2.683V
1.682ns   2.382V     1.249V     2.692V
2.903ns   2.397V     1.777V     2.696V
9.97ns    2.4V       1.8V       2.7V
[Rising Waveform]
R_fixture= 50.000000
V_fixture= 0.0
V_fixture_min= 0.0
V_fixture_max= 0.0
|time   V(typ)   V(min)   V(max)
0s        1.058mV    913.4uV    1.365mV
1.602ns   225.7uV    706.8uV    82.09mV
2.803ns   41.96mV    -4.289mV   502mV
5.125ns   392.2mV    3.934mV    1.487V
5.926ns   556.5mV    11.73mV    1.673V
7.127ns   800.5mV    31.59mV    1.777V
9.69ns    1.183V     105.1mV    1.833V
12.81ns   1.327V     217.5mV    1.847V
26.51ns   1.371V     577.4mV    1.853V
39.88ns   1.371V     610.2mV    1.852V
[Falling Waveform]
R_fixture= 50.000000
V_fixture= 2.400000
V_fixture_min= 1.800000
V_fixture_max= 2.700000
|time   V(typ)   V(min)   V(max)
0s        2.4V       1.8V       2.7V
2.002ns   2.407V     1.801V     2.659V
3.924ns   2.364V     1.805V     1.896V
5.445ns   2.139V     1.801V     1.263V
6.567ns   1.933V     1.8V       1.001V
7.768ns   1.726V     1.796V     908.1mV
11.37ns   1.218V     1.747V     836.4mV
14.73ns   1.089V     1.634V     818.1mV
28.67ns   1.012V     1.308V     806.2mV
39.88ns   1.007V     1.247V     805.7mV
[Falling Waveform]
R_fixture= 50.000000
V_fixture= 0.0
V_fixture_min= 0.0
V_fixture_max= 0.0
|time   V(typ)   V(min)   V(max)
0s        1.371V     610.2mV    1.852V
380.4ps   1.371V     610.2mV    1.725V
860.9ps   1.274V     610mV      506.3mV
1.061ns   1.019V     609.7mV    215mV
1.401ns   489.4mV    610mV      75.65mV
1.742ns   159.6mV    610.8mV    37.26mV
2.342ns   35.42mV    547.5mV    16.14mV
3.343ns   10.1mV     174.4mV    5.974mV
4.444ns   4.743mV    20.67mV    2.875mV
9.97ns    1.058mV    913.4uV    1.365mV
